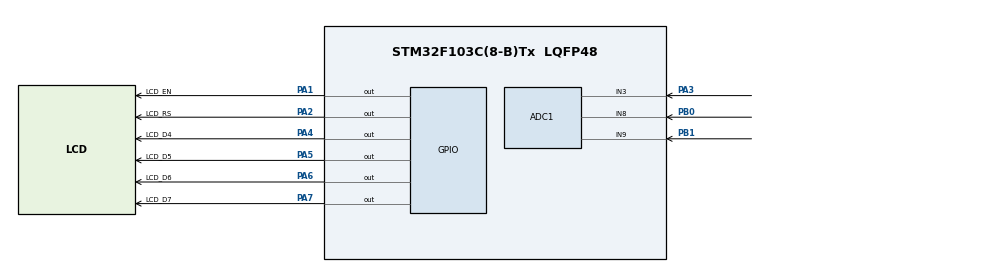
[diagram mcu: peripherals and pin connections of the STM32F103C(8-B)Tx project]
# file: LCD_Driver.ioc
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ADC1.Channel-2\#ChannelRegularConversion=ADC_CHANNEL_8
ADC1.NbrOfConversionFlag=1
ADC1.Rank-2\#ChannelRegularConversion=1
ADC1.SamplingTime-2\#ChannelRegularConversion=ADC_SAMPLETIME_1CYCLE_5
ADC1.master=1
Mcu.Family=STM32F1
Mcu.Name=STM32F103C(8-B)Tx
Mcu.Package=LQFP48
NVIC.ADC1_2_IRQn=true\:0\:0\:false\:false\:true\:true\:true\:true
NVIC.PriorityGroup=NVIC_PRIORITYGROUP_4
PA1.GPIO_Label=LCD_EN
PA1.Signal=GPIO_Output
PA13.Mode=Serial_Wire
PA13.Signal=SYS_JTMS-SWDIO
PA14.Mode=Serial_Wire
PA14.Signal=SYS_JTCK-SWCLK
PA2.GPIO_Label=LCD_RS
PA2.Signal=GPIO_Output
PA3.Signal=ADCx_IN3
PA4.GPIO_Label=LCD_D4
PA4.Signal=GPIO_Output
PA5.GPIO_Label=LCD_D5
PA5.Signal=GPIO_Output
PA6.GPIO_Label=LCD_D6
PA6.Signal=GPIO_Output
PA7.GPIO_Label=LCD_D7
PA7.Signal=GPIO_Output
PB0.Signal=ADCx_IN8
PB1.Signal=ADCx_IN9
PD0-OSC_IN.Mode=HSE-External-Oscillator
PD0-OSC_IN.Signal=RCC_OSC_IN
PD1-OSC_OUT.Mode=HSE-External-Oscillator
PD1-OSC_OUT.Signal=RCC_OSC_OUT
ProjectManager.HeapSize=0x200
ProjectManager.StackSize=0x400
ProjectManager.TargetToolchain=STM32CubeIDE
RCC.AHBFreq_Value=8000000
RCC.APB1Freq_Value=8000000
RCC.APB1TimFreq_Value=8000000
RCC.APB2Freq_Value=8000000
RCC.APB2TimFreq_Value=8000000
RCC.HCLKFreq_Value=8000000
RCC.SYSCLKFreq_VALUE=8000000
RCC.SYSCLKSource=RCC_SYSCLKSOURCE_PLLCLK
RCC.USBFreq_Value=8000000
SH.ADCx_IN3.0=ADC1_IN3,IN3
SH.ADCx_IN8.0=ADC1_IN8,IN8
SH.ADCx_IN9.0=ADC1_IN9,IN9
board=custom

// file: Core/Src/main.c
/* USER CODE BEGIN Header */
/**
  ******************************************************************************
  * @file           : main.c
  * @brief          : Main program body
  ******************************************************************************
  */
/* USER CODE END Header */
#include "main.h"
#include <stdio.h>
#include <string.h>
#include "LCD.h"

ADC_HandleTypeDef hadc1;

void SystemClock_Config(void);
static void MX_GPIO_Init(void);
static void MX_ADC1_Init(void);
uint16_t Read_ADC(uint32_t channel);

int main(void)
{
  HAL_Init();
  SystemClock_Config();
  MX_GPIO_Init();
  MX_ADC1_Init();

  lcd_init(_LCD_4BIT, _LCD_FONT_5x8, _LCD_2LINE);
  HAL_Delay(500);
  lcd_clear();

  char buffer[32];

  while (1)
  {
    uint16_t adc_PA3 = Read_ADC(ADC_CHANNEL_3);  // PA3
    uint16_t adc_PB0 = Read_ADC(ADC_CHANNEL_8);  // PB0
    uint16_t adc_PB1 = Read_ADC(ADC_CHANNEL_9);  // PB1

    lcd_clear();
    sprintf(buffer, "PA3: %2d", adc_PA3);
    lcd_print(1, 1, buffer);
    sprintf(buffer, "PB0:%2dPB1:%2d", adc_PB0, adc_PB1);
    lcd_print(2, 1, buffer);

    HAL_Delay(2000);
  }
}

/**
  * @brief ADC değeri okuma fonksiyonu (tek kanal)
  */
uint16_t Read_ADC(uint32_t channel)
{
  ADC_ChannelConfTypeDef sConfig = {0};
  sConfig.Channel = channel;
  sConfig.Rank = ADC_REGULAR_RANK_1;
  sConfig.SamplingTime = ADC_SAMPLETIME_28CYCLES_5;  // Daha uzun örnekleme süresi

  if (HAL_ADC_ConfigChannel(&hadc1, &sConfig) != HAL_OK)
  {
    Error_Handler();
  }

  HAL_ADC_Start(&hadc1);
  if(HAL_ADC_PollForConversion(&hadc1, 10) != HAL_OK)  // timeout 10ms
  {
    return 0;  // Hata durumunda 0 döndür
  }
  uint16_t value = HAL_ADC_GetValue(&hadc1);
  HAL_ADC_Stop(&hadc1);

  return value;
}

/* ADC1 Initialization */
static void MX_ADC1_Init(void)
{
  ADC_ChannelConfTypeDef sConfig = {0};

  hadc1.Instance = ADC1;
  hadc1.Init.ScanConvMode = ADC_SCAN_DISABLE;  // Tek kanal okuma
  hadc1.Init.ContinuousConvMode = DISABLE;
  hadc1.Init.DiscontinuousConvMode = DISABLE;
  hadc1.Init.ExternalTrigConv = ADC_SOFTWARE_START;
  hadc1.Init.DataAlign = ADC_DATAALIGN_RIGHT;
  hadc1.Init.NbrOfConversion = 1;
  if (HAL_ADC_Init(&hadc1) != HAL_OK)
  {
    Error_Handler();
  }

  // Başlangıçta kanal 3 (PA3) seçiliyor
  sConfig.Channel = ADC_CHANNEL_3;
  sConfig.Rank = ADC_REGULAR_RANK_1;
  sConfig.SamplingTime = ADC_SAMPLETIME_28CYCLES_5;
  if (HAL_ADC_ConfigChannel(&hadc1, &sConfig) != HAL_OK)
  {
    Error_Handler();
  }
}

void SystemClock_Config(void)
{
  RCC_OscInitTypeDef RCC_OscInitStruct = {0};
  RCC_ClkInitTypeDef RCC_ClkInitStruct = {0};
  RCC_PeriphCLKInitTypeDef PeriphClkInit = {0};

  RCC_OscInitStruct.OscillatorType = RCC_OSCILLATORTYPE_HSI;
  RCC_OscInitStruct.HSIState = RCC_HSI_ON;
  RCC_OscInitStruct.HSICalibrationValue = RCC_HSICALIBRATION_DEFAULT;
  RCC_OscInitStruct.PLL.PLLState = RCC_PLL_ON;
  RCC_OscInitStruct.PLL.PLLSource = RCC_PLLSOURCE_HSI_DIV2;
  RCC_OscInitStruct.PLL.PLLMUL = RCC_PLL_MUL8;
  if (HAL_RCC_OscConfig(&RCC_OscInitStruct) != HAL_OK) { Error_Handler(); }

  RCC_ClkInitStruct.ClockType = RCC_CLOCKTYPE_HCLK|RCC_CLOCKTYPE_SYSCLK
                                |RCC_CLOCKTYPE_PCLK1|RCC_CLOCKTYPE_PCLK2;
  RCC_ClkInitStruct.SYSCLKSource = RCC_SYSCLKSOURCE_PLLCLK;
  RCC_ClkInitStruct.AHBCLKDivider = RCC_SYSCLK_DIV1;
  RCC_ClkInitStruct.APB1CLKDivider = RCC_HCLK_DIV1;
  RCC_ClkInitStruct.APB2CLKDivider = RCC_HCLK_DIV1;
  if (HAL_RCC_ClockConfig(&RCC_ClkInitStruct, FLASH_LATENCY_1) != HAL_OK) { Error_Handler(); }

  PeriphClkInit.PeriphClockSelection = RCC_PERIPHCLK_ADC;
  PeriphClkInit.AdcClockSelection = RCC_ADCPCLK2_DIV4;
  if (HAL_RCCEx_PeriphCLKConfig(&PeriphClkInit) != HAL_OK) { Error_Handler(); }
}

/* GPIO Initialization */
static void MX_GPIO_Init(void)
{
  GPIO_InitTypeDef GPIO_InitStruct = {0};

  __HAL_RCC_GPIOD_CLK_ENABLE();
  __HAL_RCC_GPIOA_CLK_ENABLE();
  __HAL_RCC_GPIOB_CLK_ENABLE();

  // LCD pinleri
  HAL_GPIO_WritePin(GPIOA, LCD_EN_Pin|LCD_RS_Pin|LCD_D4_Pin|LCD_D5_Pin
                          |LCD_D6_Pin|LCD_D7_Pin, GPIO_PIN_RESET);

  GPIO_InitStruct.Pin = LCD_EN_Pin|LCD_RS_Pin|LCD_D4_Pin|LCD_D5_Pin
                          |LCD_D6_Pin|LCD_D7_Pin;
  GPIO_InitStruct.Mode = GPIO_MODE_OUTPUT_PP;
  GPIO_InitStruct.Pull = GPIO_NOPULL;
  GPIO_InitStruct.Speed = GPIO_SPEED_FREQ_LOW;
  HAL_GPIO_Init(GPIOA, &GPIO_InitStruct);

  // ADC giriş pinlerini analog moda ayarla
  // PA3
  GPIO_InitStruct.Pin = GPIO_PIN_3;
  GPIO_InitStruct.Mode = GPIO_MODE_ANALOG;
  GPIO_InitStruct.Pull = GPIO_NOPULL;
  HAL_GPIO_Init(GPIOA, &GPIO_InitStruct);

  // PB0
  GPIO_InitStruct.Pin = GPIO_PIN_0;
  GPIO_InitStruct.Mode = GPIO_MODE_ANALOG;
  GPIO_InitStruct.Pull = GPIO_NOPULL;
  HAL_GPIO_Init(GPIOB, &GPIO_InitStruct);

  // PB1
  GPIO_InitStruct.Pin = GPIO_PIN_1;
  GPIO_InitStruct.Mode = GPIO_MODE_ANALOG;
  GPIO_InitStruct.Pull = GPIO_NOPULL;
  HAL_GPIO_Init(GPIOB, &GPIO_InitStruct);
}

/* Error Handler */
void Error_Handler(void)
{
  __disable_irq();
  while (1) {}
}
